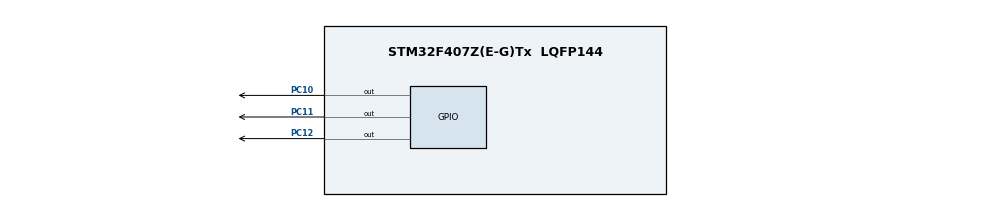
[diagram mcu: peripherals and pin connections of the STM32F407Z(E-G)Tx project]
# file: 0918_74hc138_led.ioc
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Mcu.Family=STM32F4
Mcu.Name=STM32F407Z(E-G)Tx
Mcu.Package=LQFP144
NVIC.PriorityGroup=NVIC_PRIORITYGROUP_4
PA13.Mode=Serial_Wire
PA13.Signal=SYS_JTMS-SWDIO
PA14.Mode=Serial_Wire
PA14.Signal=SYS_JTCK-SWCLK
PC10.Signal=GPIO_Output
PC11.Signal=GPIO_Output
PC12.Signal=GPIO_Output
PH0-OSC_IN.Mode=HSE-External-Oscillator
PH0-OSC_IN.Signal=RCC_OSC_IN
PH1-OSC_OUT.Mode=HSE-External-Oscillator
PH1-OSC_OUT.Signal=RCC_OSC_OUT
ProjectManager.HeapSize=0x200
ProjectManager.StackSize=0x400
ProjectManager.TargetToolchain=CMake
RCC.48MHZClocksFreq_Value=84000000
RCC.AHBFreq_Value=168000000
RCC.APB1CLKDivider=RCC_HCLK_DIV4
RCC.APB1Freq_Value=42000000
RCC.APB1TimFreq_Value=84000000
RCC.APB2CLKDivider=RCC_HCLK_DIV2
RCC.APB2Freq_Value=84000000
RCC.APB2TimFreq_Value=168000000
RCC.CortexFreq_Value=168000000
RCC.HCLKFreq_Value=168000000
RCC.HSE_VALUE=8000000
RCC.HSI_VALUE=16000000
RCC.LSE_VALUE=32768
RCC.PLLM=4
RCC.PLLN=168
RCC.PLLSourceVirtual=RCC_PLLSOURCE_HSE
RCC.SYSCLKFreq_VALUE=168000000
RCC.SYSCLKSource=RCC_SYSCLKSOURCE_PLLCLK
RCC.VCOOutputFreq_Value=336000000
board=custom

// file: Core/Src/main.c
/* USER CODE BEGIN Header */
/**
  ******************************************************************************
  * @file           : main.c
  * @brief          : Main program body
  ******************************************************************************
  * @attention
  *
  * Copyright (c) 2025 STMicroelectronics.
  * All rights reserved.
  *
  * This software is licensed under terms that can be found in the LICENSE file
  * in the root directory of this software component.
  * If no LICENSE file comes with this software, it is provided AS-IS.
  *
  ******************************************************************************
  */
/* USER CODE END Header */
#include "main.h"

void SystemClock_Config(void);

/* USER CODE BEGIN 0 */

void IC74HC138_Init(void)
{
  GPIO_InitTypeDef GPIO_InitStruct = {0};

  /* GPIO Ports Clock Enable */
  __HAL_RCC_GPIOC_CLK_ENABLE();

  /*Configure GPIO pin Output Level */
  HAL_GPIO_WritePin(GPIOC, GPIO_PIN_10|GPIO_PIN_11|GPIO_PIN_12,GPIO_PIN_RESET);

  /*Configure GPIO pins : PG3 PG4 PG7 PG10 */
  GPIO_InitStruct.Pin = GPIO_PIN_10|GPIO_PIN_11|GPIO_PIN_12;
  GPIO_InitStruct.Mode = GPIO_MODE_OUTPUT_PP;
  GPIO_InitStruct.Pull = GPIO_NOPULL;
  GPIO_InitStruct.Speed = GPIO_SPEED_FREQ_LOW;
  HAL_GPIO_Init(GPIOC, &GPIO_InitStruct);

}
void  Light(uint8_t Data)
{
  if (Data<8)
  {
    uint16_t temp=GPIOC->ODR;
    temp &=0xE3FF;
    temp |= (uint16_t) Data<<10;
    GPIOC->ODR=temp;
  }

}

/* USER CODE END 0 */

int main(void)
{

  /* MCU Configuration--------------------------------------------------------*/

  /* Reset of all peripherals, Initializes the Flash interface and the Systick. */
  HAL_Init();

  /* Configure the system clock */
  SystemClock_Config();

  /* Initialize all configured peripherals */

  /* USER CODE BEGIN 2 */
 IC74HC138_Init();
  uint16_t i=0;
  /* USER CODE END 2 */

  /* Infinite loop */
  /* USER CODE BEGIN WHILE */
  while (1)
  {

		Light(i);
		HAL_Delay(1000);
		i++;
		if (i>7) i=059+=5;
    /* USER CODE END WHILE */

  }
}

void SystemClock_Config(void)
{
  RCC_OscInitTypeDef RCC_OscInitStruct = {0};
  RCC_ClkInitTypeDef RCC_ClkInitStruct = {0};

  /** Configure the main internal regulator output voltage
  */
  __HAL_RCC_PWR_CLK_ENABLE();
  __HAL_PWR_VOLTAGESCALING_CONFIG(PWR_REGULATOR_VOLTAGE_SCALE1);

  /** Initializes the RCC Oscillators according to the specified parameters
  * in the RCC_OscInitTypeDef structure.
  */
  RCC_OscInitStruct.OscillatorType = RCC_OSCILLATORTYPE_HSI;
  RCC_OscInitStruct.HSIState = RCC_HSI_ON;
  RCC_OscInitStruct.HSICalibrationValue = RCC_HSICALIBRATION_DEFAULT;
  RCC_OscInitStruct.PLL.PLLState = RCC_PLL_NONE;
  if (HAL_RCC_OscConfig(&RCC_OscInitStruct) != HAL_OK)
  {
    Error_Handler();
  }

  /** Initializes the CPU, AHB and APB buses clocks
  */
  RCC_ClkInitStruct.ClockType = RCC_CLOCKTYPE_HCLK|RCC_CLOCKTYPE_SYSCLK
                              |RCC_CLOCKTYPE_PCLK1|RCC_CLOCKTYPE_PCLK2;
  RCC_ClkInitStruct.SYSCLKSource = RCC_SYSCLKSOURCE_HSI;
  RCC_ClkInitStruct.AHBCLKDivider = RCC_SYSCLK_DIV1;
  RCC_ClkInitStruct.APB1CLKDivider = RCC_HCLK_DIV1;
  RCC_ClkInitStruct.APB2CLKDivider = RCC_HCLK_DIV1;

  if (HAL_RCC_ClockConfig(&RCC_ClkInitStruct, FLASH_LATENCY_0) != HAL_OK)
  {
    Error_Handler();
  }
}

void Error_Handler(void)
{
  __disable_irq();
  while (1)
  {
  }
}
